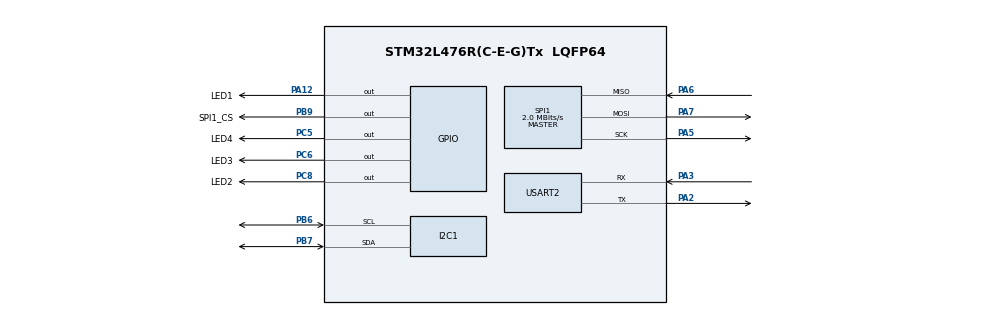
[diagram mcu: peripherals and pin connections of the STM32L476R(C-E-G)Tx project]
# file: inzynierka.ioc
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I2C1.Timing=0x00100D14
Mcu.Family=STM32L4
Mcu.Name=STM32L476R(C-E-G)Tx
Mcu.Package=LQFP64
NVIC.PriorityGroup=NVIC_PRIORITYGROUP_4
PA12.GPIO_Label=LED1
PA12.Signal=GPIO_Output
PA13\ (JTMS-SWDIO).Mode=Trace_Asynchronous_SW
PA13\ (JTMS-SWDIO).Signal=SYS_JTMS-SWDIO
PA14\ (JTCK-SWCLK).Mode=Trace_Asynchronous_SW
PA14\ (JTCK-SWCLK).Signal=SYS_JTCK-SWCLK
PA2.Mode=Asynchronous
PA2.Signal=USART2_TX
PA3.Mode=Asynchronous
PA3.Signal=USART2_RX
PA5.Mode=Full_Duplex_Master
PA5.Signal=SPI1_SCK
PA6.Mode=Full_Duplex_Master
PA6.Signal=SPI1_MISO
PA7.Mode=Full_Duplex_Master
PA7.Signal=SPI1_MOSI
PB3\ (JTDO-TRACESWO).Mode=Trace_Asynchronous_SW
PB3\ (JTDO-TRACESWO).Signal=SYS_JTDO-SWO
PB6.Mode=I2C
PB6.Signal=I2C1_SCL
PB7.Mode=I2C
PB7.Signal=I2C1_SDA
PB9.GPIO_Label=SPI1_CS
PB9.Signal=GPIO_Output
PC5.GPIO_Label=LED4
PC5.Signal=GPIO_Output
PC6.GPIO_Label=LED3
PC6.Signal=GPIO_Output
PC8.GPIO_Label=LED2
PC8.Signal=GPIO_Output
ProjectManager.HeapSize=0x200
ProjectManager.StackSize=0x400
ProjectManager.TargetToolchain=STM32CubeIDE
RCC.HSE_VALUE=8000000
RCC.HSI_VALUE=16000000
RCC.LSE_VALUE=32768
RCC.MSI_VALUE=4000000
RCC.VCOOutputFreq_Value=32000000
SPI1.CalculateBaudRate=2.0 MBits/s
SPI1.DataSize=SPI_DATASIZE_8BIT
SPI1.Direction=SPI_DIRECTION_2LINES
SPI1.Mode=SPI_MODE_MASTER
SPI1.VirtualType=VM_MASTER
USART2.VirtualMode-Asynchronous=VM_ASYNC
board=custom

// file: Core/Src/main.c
/* USER CODE BEGIN Header */
/**
  ******************************************************************************
  * @file           : main.c
  * @brief          : Main program body
  ******************************************************************************
  * @attention
  *
  * Copyright (c) 2026 STMicroelectronics.
  * All rights reserved.
  *
  * This software is licensed under terms that can be found in the LICENSE file
  * in the root directory of this software component.
  * If no LICENSE file comes with this software, it is provided AS-IS.
  *
  ******************************************************************************
  */
/* USER CODE END Header */
#include "main.h"

I2C_HandleTypeDef hi2c1;

SPI_HandleTypeDef hspi1;

UART_HandleTypeDef huart2;

void SystemClock_Config(void);
static void MX_GPIO_Init(void);
static void MX_I2C1_Init(void);
static void MX_SPI1_Init(void);
static void MX_USART2_UART_Init(void);

int main(void)
{

  /* USER CODE BEGIN 1 */
	//uint8_t image_buffer[50000];   /* dostosuj rozmiar do formatu/rozdzielczosci */
 	//uint32_t image_len = 0;

  /* USER CODE END 1 */

  /* MCU Configuration--------------------------------------------------------*/

  /* Reset of all peripherals, Initializes the Flash interface and the Systick. */

	HAL_Init();

  /* USER CODE BEGIN Init */
  const sensor_reg SPI_fifo_prepare[] = {
      {0x04, 0x01},   // FIFO_CLEAR_MASK
      {0x04, 0x10},   // FIFO_RDPTR_RST_MASK
      {0x04, 0x20},   // FIFO_WRPTR_RST_MASK
  };

  /* ---- GRUPA 4: start przechwytywania ---- */
  const sensor_reg SPI_start_capture[] = {
      {0x04, 0x02},   // FIFO_START_MASK
  };

  /* USER CODE END Init */

  /* Configure the system clock */
  SystemClock_Config();

  /* USER CODE BEGIN SysInit */
  i2c_bus_recovery();
  /* USER CODE END SysInit */
  HAL_Delay(100);
  /* Initialize all configured peripherals */
  MX_GPIO_Init();
  MX_I2C1_Init();
  MX_SPI1_Init();
  MX_USART2_UART_Init();

  //HAL_GPIO_WritePin(           );

  engineInit();                 // raz, na starcie main()
  //test();
  move(200, 1, 1);              // silnik 1, do przodu, 200 mikrokroków
  move(200, 1, 0);               // silnik 1, do tyłu, 200 mikrokroków
  move(200, 2, 1);               // silnik 2, do przodu

  arducam_check_version();

  HAL_Delay(100);
  i2c_flash_test();
  i2c_cam_init_test();
  i2c_camera_init_test();      /* pelna konfiguracja JPEG + kontrast */
  HAL_Delay(1000);              /* stabilizacja po pelnej inicjalizacji */

  arducam_check_version();      /* powinno pokazac 0x40 */
  arducam_spi_test();           /* powinno pokazac before=0x00 after=0x55 */

  arducam_capture_photo(&huart2);
  /* USER CODE END 2 */

  /* Infinite loop */
  while (1)
  {

  }
}

void SystemClock_Config(void)
{
  RCC_OscInitTypeDef RCC_OscInitStruct = {0};
  RCC_ClkInitTypeDef RCC_ClkInitStruct = {0};

  /** Configure the main internal regulator output voltage
  */
  if (HAL_PWREx_ControlVoltageScaling(PWR_REGULATOR_VOLTAGE_SCALE1) != HAL_OK)
  {
    Error_Handler();
  }

  /** Initializes the RCC Oscillators according to the specified parameters
  * in the RCC_OscInitTypeDef structure.
  */
  RCC_OscInitStruct.OscillatorType = RCC_OSCILLATORTYPE_MSI;
  RCC_OscInitStruct.MSIState = RCC_MSI_ON;
  RCC_OscInitStruct.MSICalibrationValue = 0;
  RCC_OscInitStruct.MSIClockRange = RCC_MSIRANGE_6;
  RCC_OscInitStruct.PLL.PLLState = RCC_PLL_NONE;
  if (HAL_RCC_OscConfig(&RCC_OscInitStruct) != HAL_OK)
  {
    Error_Handler();
  }

  /** Initializes the CPU, AHB and APB buses clocks
  */
  RCC_ClkInitStruct.ClockType = RCC_CLOCKTYPE_HCLK|RCC_CLOCKTYPE_SYSCLK
                              |RCC_CLOCKTYPE_PCLK1|RCC_CLOCKTYPE_PCLK2;
  RCC_ClkInitStruct.SYSCLKSource = RCC_SYSCLKSOURCE_MSI;
  RCC_ClkInitStruct.AHBCLKDivider = RCC_SYSCLK_DIV1;
  RCC_ClkInitStruct.APB1CLKDivider = RCC_HCLK_DIV1;
  RCC_ClkInitStruct.APB2CLKDivider = RCC_HCLK_DIV1;

  if (HAL_RCC_ClockConfig(&RCC_ClkInitStruct, FLASH_LATENCY_0) != HAL_OK)
  {
    Error_Handler();
  }
}

static void MX_I2C1_Init(void)
{

  hi2c1.Instance = I2C1;
  hi2c1.Init.Timing = 0x00100D14;
  hi2c1.Init.OwnAddress1 = 0;
  hi2c1.Init.AddressingMode = I2C_ADDRESSINGMODE_7BIT;
  hi2c1.Init.DualAddressMode = I2C_DUALADDRESS_DISABLE;
  hi2c1.Init.OwnAddress2 = 0;
  hi2c1.Init.OwnAddress2Masks = I2C_OA2_NOMASK;
  hi2c1.Init.GeneralCallMode = I2C_GENERALCALL_DISABLE;
  hi2c1.Init.NoStretchMode = I2C_NOSTRETCH_DISABLE;
  if (HAL_I2C_Init(&hi2c1) != HAL_OK)
  {
    Error_Handler();
  }

  /** Configure Analogue filter
  */
  if (HAL_I2CEx_ConfigAnalogFilter(&hi2c1, I2C_ANALOGFILTER_ENABLE) != HAL_OK)
  {
    Error_Handler();
  }

  /** Configure Digital filter
  */
  if (HAL_I2CEx_ConfigDigitalFilter(&hi2c1, 0) != HAL_OK)
  {
    Error_Handler();
  }

}

static void MX_SPI1_Init(void)
{

  /* SPI1 parameter configuration*/
  hspi1.Instance = SPI1;
  hspi1.Init.Mode = SPI_MODE_MASTER;
  hspi1.Init.Direction = SPI_DIRECTION_2LINES;
  hspi1.Init.DataSize = SPI_DATASIZE_8BIT;
  hspi1.Init.CLKPolarity = SPI_POLARITY_LOW;
  hspi1.Init.CLKPhase = SPI_PHASE_1EDGE;
  hspi1.Init.NSS = SPI_NSS_SOFT;
  hspi1.Init.BaudRatePrescaler = SPI_BAUDRATEPRESCALER_64;
  hspi1.Init.FirstBit = SPI_FIRSTBIT_MSB;
  hspi1.Init.TIMode = SPI_TIMODE_DISABLE;
  hspi1.Init.CRCCalculation = SPI_CRCCALCULATION_DISABLE;
  hspi1.Init.CRCPolynomial = 7;
  hspi1.Init.CRCLength = SPI_CRC_LENGTH_DATASIZE;
  hspi1.Init.NSSPMode = SPI_NSS_PULSE_ENABLE;
  if (HAL_SPI_Init(&hspi1) != HAL_OK)
  {
    Error_Handler();
  }

}

static void MX_USART2_UART_Init(void)
{

  huart2.Instance = USART2;
  huart2.Init.BaudRate = 115200;
  huart2.Init.WordLength = UART_WORDLENGTH_8B;
  huart2.Init.StopBits = UART_STOPBITS_1;
  huart2.Init.Parity = UART_PARITY_NONE;
  huart2.Init.Mode = UART_MODE_TX_RX;
  huart2.Init.HwFlowCtl = UART_HWCONTROL_NONE;
  huart2.Init.OverSampling = UART_OVERSAMPLING_16;
  huart2.Init.OneBitSampling = UART_ONE_BIT_SAMPLE_DISABLE;
  huart2.AdvancedInit.AdvFeatureInit = UART_ADVFEATURE_NO_INIT;
  if (HAL_UART_Init(&huart2) != HAL_OK)
  {
    Error_Handler();
  }

}

static void MX_GPIO_Init(void)
{
  GPIO_InitTypeDef GPIO_InitStruct = {0};

  /* GPIO Ports Clock Enable */
  __HAL_RCC_GPIOA_CLK_ENABLE();
  __HAL_RCC_GPIOC_CLK_ENABLE();
  __HAL_RCC_GPIOB_CLK_ENABLE();

  /*Configure GPIO pin Output Level */
  HAL_GPIO_WritePin(GPIOC, LED4_Pin|LED3_Pin|LED2_Pin, GPIO_PIN_RESET);

  /*Configure GPIO pin Output Level */
  HAL_GPIO_WritePin(LED1_GPIO_Port, LED1_Pin, GPIO_PIN_RESET);

  /*Configure GPIO pin Output Level */
  HAL_GPIO_WritePin(SPI1_CS_GPIO_Port, SPI1_CS_Pin, GPIO_PIN_RESET);

  /* GPIOA */
  HAL_GPIO_WritePin(GPIOA,
                    STEP1_Pin |
                    DIR1_Pin  |
                    MS12_Pin  |
                    MS22_Pin  |
                    MS11_Pin,
                    GPIO_PIN_RESET);

  /* GPIOB */
  HAL_GPIO_WritePin(GPIOB,
                    STEP2_Pin |
                    DIR2_Pin  |
                    MS31_Pin  |
                    MS21_Pin  |
                    SLEEP_Pin,
                    GPIO_PIN_RESET);

  /* GPIOC */
  HAL_GPIO_WritePin(GPIOC,
                    MS32_Pin |
                    RESET_Pin |
                    ENNABLE_Pin,
                    GPIO_PIN_RESET);

  /*Configure GPIO pins : LED4_Pin LED3_Pin LED2_Pin */
  GPIO_InitStruct.Pin = LED4_Pin|LED3_Pin|LED2_Pin | MS32_Pin |
          RESET_Pin |
          ENNABLE_Pin;
  GPIO_InitStruct.Mode = GPIO_MODE_OUTPUT_PP;
  GPIO_InitStruct.Pull = GPIO_NOPULL;
  GPIO_InitStruct.Speed = GPIO_SPEED_FREQ_LOW;
  HAL_GPIO_Init(GPIOC, &GPIO_InitStruct);

  /*Configure GPIO pin : LED1_Pin */
  GPIO_InitStruct.Pin = LED1_Pin | STEP1_Pin |
          DIR1_Pin  |
          MS12_Pin  |
          MS22_Pin  |
          MS11_Pin;
  GPIO_InitStruct.Mode = GPIO_MODE_OUTPUT_PP;
  GPIO_InitStruct.Pull = GPIO_NOPULL;
  GPIO_InitStruct.Speed = GPIO_SPEED_FREQ_LOW;
  HAL_GPIO_Init(GPIOA, &GPIO_InitStruct);

  /*Configure GPIO pin : SPI1_CS_Pin */
  GPIO_InitStruct.Pin = SPI1_CS_Pin | STEP2_Pin |
          DIR2_Pin  |
          MS31_Pin  |
          MS21_Pin  |
          SLEEP_Pin;
  GPIO_InitStruct.Mode = GPIO_MODE_OUTPUT_PP;
  GPIO_InitStruct.Pull = GPIO_NOPULL;
  GPIO_InitStruct.Speed = GPIO_SPEED_FREQ_LOW;
  HAL_GPIO_Init(GPIOB, &GPIO_InitStruct);

  /* USER CODE BEGIN MX_GPIO_Init_2 */
  HAL_GPIO_WritePin(GPIOC, LED4_Pin|LED3_Pin|LED2_Pin, GPIO_PIN_RESET);
  HAL_GPIO_WritePin(GPIOA, GPIO_PIN_0|STEP1_Pin|DIR1_Pin|MS12_Pin
                          |MS22_Pin|MS32_Pin|GPIO_PIN_8|DIR2_Pin, GPIO_PIN_RESET);
  HAL_GPIO_WritePin(ENNABLE_GPIO_Port, ENNABLE_Pin, GPIO_PIN_RESET);
  HAL_GPIO_WritePin(GPIOB, MS21_Pin|SLEEP_Pin|MS11_Pin|RESET_Pin, GPIO_PIN_RESET);
  /*Configure GPIO pin Output Level */
  HAL_GPIO_WritePin(LED1_GPIO_Port, LED1_Pin, GPIO_PIN_RESET);
  /* USER CODE END MX_GPIO_Init_2 */
}

void Error_Handler(void)
{
  __disable_irq();
  while (1)
  {
  }
}
